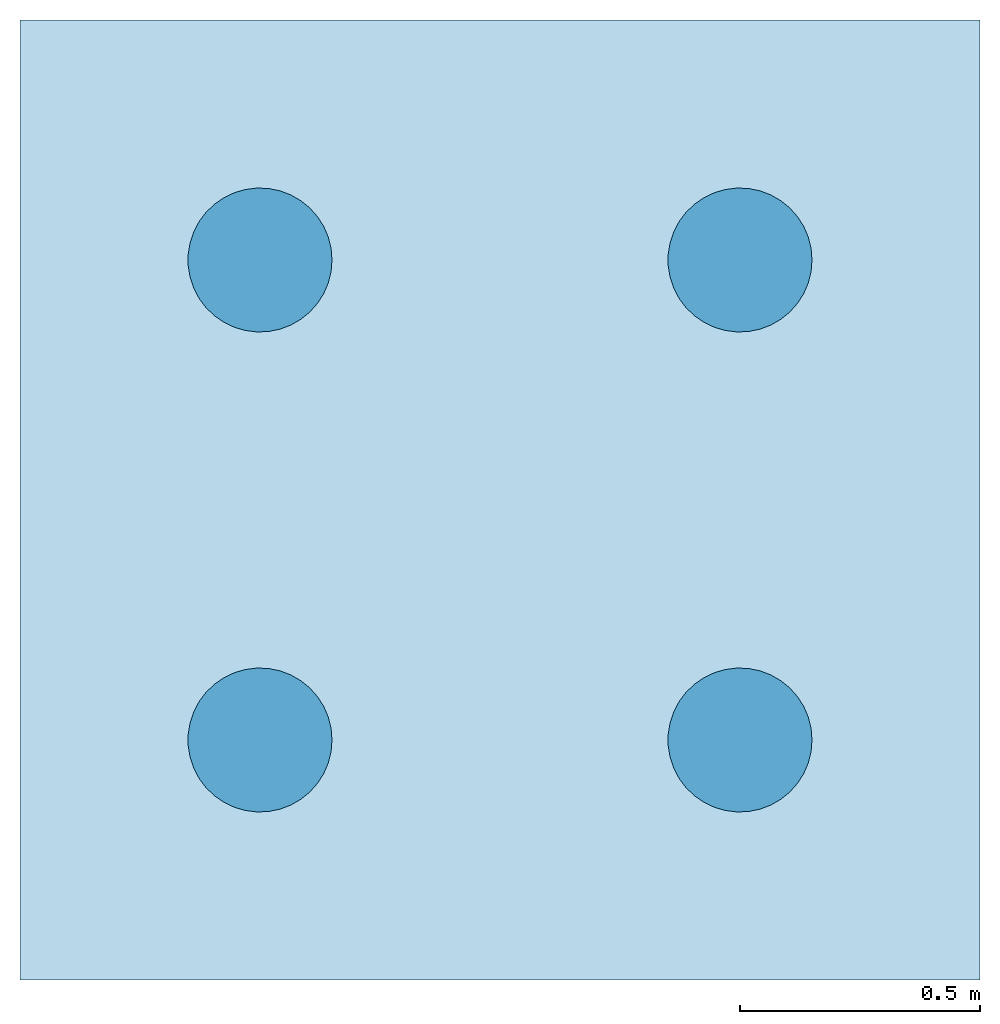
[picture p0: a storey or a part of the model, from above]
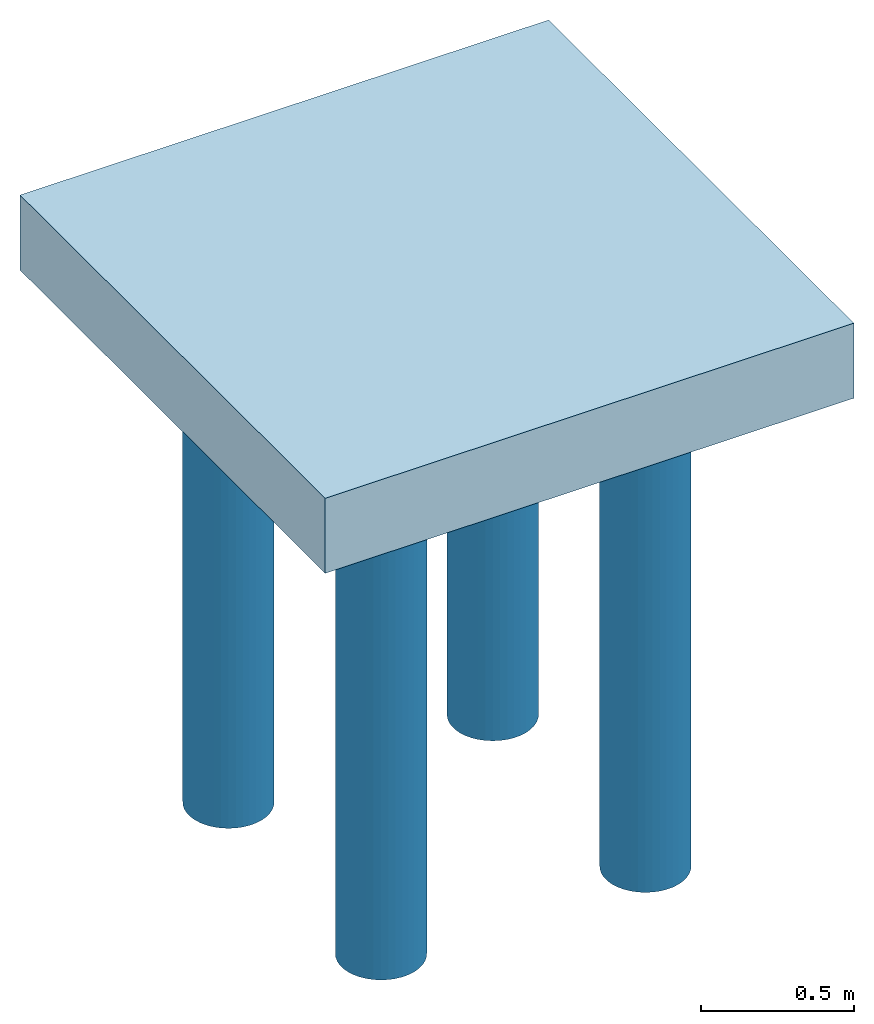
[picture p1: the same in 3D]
Properties of the parts of a building model (IFC4)

# File
Description: IFC4
Time: 2025-08-18T09:11:46
Made in: IfcPlusPlus

# IfcBuildingStorey, Radier
LongName: Radier; Elevation: 0 cm

# IfcPile (4)
In: Radier
Material: Concreto
Pset_ConcreteElementGeneral - ConcreteCover: 3 cm; ConstructionMethod: InSitu; ExposureClass: 2; StrengthClass: C-25
Pset_PileCommon - Reference: Estaca circular Ø30-4M - Concreto C-25
Name
E1
E2
E3
E4

# IfcSlab, L1
In: Radier
PredefinedType: FLOOR; Material: Concreto
Pset_ConcreteElementGeneral - ConcreteCover: 3 cm; ConstructionMethod: InSitu; ExposureClass: 2; StrengthClass: C-25
AltoQi_Eberick_Elemento - Elemento: Radier; Tipo: Maciça; Elevação: 30 cm; Espessura: 30 cm
AltoQi_Eberick_Padrão - Ambiente: Contato com solo; Cobrimento: 3 cm; Classe de concreto: C-25
AltoQi_Eberick_Cargas - Revestimento (G2): 250.5; Adicional (G2): 0; Solo (S): 0; Acidental (Q): 1250; Água (A): 0; Subpressão (AS): 0
Pset_SlabCommon - Reference: Laje de fundação C-25 - h=30cm; LoadBearing: yes; IsExternal: yes; PitchAngle: 0 rad
